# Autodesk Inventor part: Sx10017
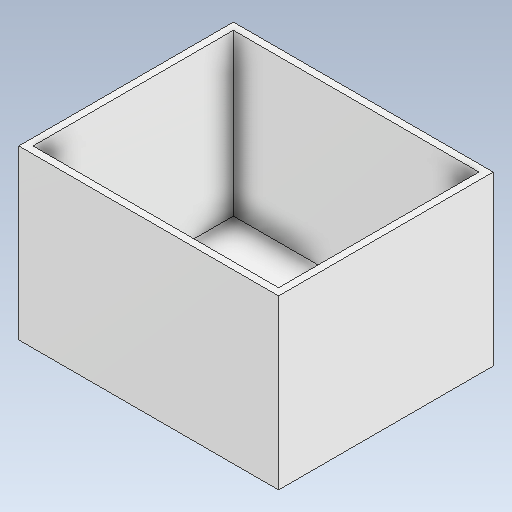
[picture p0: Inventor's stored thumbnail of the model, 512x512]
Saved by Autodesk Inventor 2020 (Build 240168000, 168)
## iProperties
Created: 2021-02
Part Number: Sx10017
Material: Generico
Document SubType Name: Modeling
Designer: zambolin
Density: 1 g/cm^3
Appearance: Default
Author: zambolin
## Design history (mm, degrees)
feature "Solido2"
node "Solido1"
